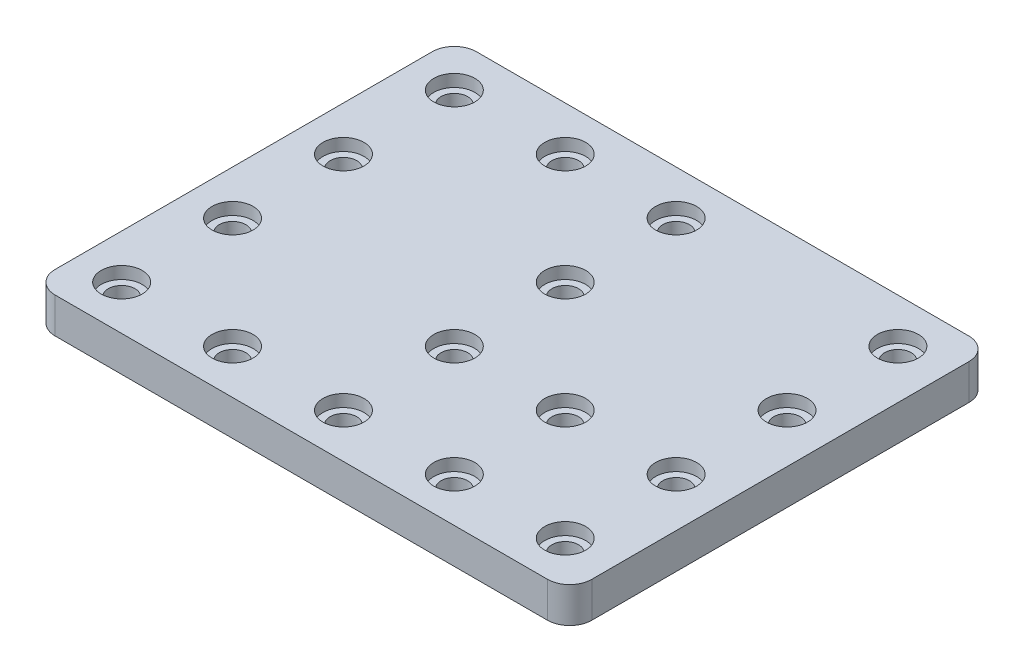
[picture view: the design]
ISO-10303-21;
HEADER;
FILE_DESCRIPTION(('STEP AP214'),'2;1');
FILE_NAME('part.step','',(''),(''),'','','');
FILE_SCHEMA(('AUTOMOTIVE_DESIGN { 1 0 10303 214 1 1 1 1 }'));
ENDSEC;
DATA;
#1=APPLICATION_CONTEXT('core data for automotive mechanical design processes');
#2=APPLICATION_PROTOCOL_DEFINITION('international standard','automotive_design',2000,#1);
#3=PRODUCT_CONTEXT('',#1,'mechanical');
#4=PRODUCT('Part','Part','',(#3));
#5=PRODUCT_RELATED_PRODUCT_CATEGORY('part','',(#4));
#6=PRODUCT_DEFINITION_FORMATION('','',#4);
#7=PRODUCT_DEFINITION_CONTEXT('part definition',#1,'design');
#8=PRODUCT_DEFINITION('design','',#6,#7);
#9=PRODUCT_DEFINITION_SHAPE('','',#8);
#10=(LENGTH_UNIT() NAMED_UNIT(*) SI_UNIT(.MILLI.,.METRE.));
#11=(NAMED_UNIT(*) PLANE_ANGLE_UNIT() SI_UNIT($,.RADIAN.));
#12=(NAMED_UNIT(*) SI_UNIT($,.STERADIAN.) SOLID_ANGLE_UNIT());
#13=UNCERTAINTY_MEASURE_WITH_UNIT(LENGTH_MEASURE(1.E-05),#10,'distance_accuracy_value','');
#14=(GEOMETRIC_REPRESENTATION_CONTEXT(3) GLOBAL_UNCERTAINTY_ASSIGNED_CONTEXT((#13)) GLOBAL_UNIT_ASSIGNED_CONTEXT((#10,
#11,#12)) REPRESENTATION_CONTEXT('',''));
#15=CARTESIAN_POINT('',(0.,0.,0.));
#16=DIRECTION('',(0.,0.,1.));
#17=DIRECTION('',(1.,0.,0.));
#18=AXIS2_PLACEMENT_3D('',#15,#16,#17);
#19=CARTESIAN_POINT('',(10.,16.,-10.));
#20=DIRECTION('',(0.,-1.,0.));
#21=DIRECTION('',(0.,0.,-1.));
#22=AXIS2_PLACEMENT_3D('',#19,#20,#21);
#23=CYLINDRICAL_SURFACE('',#22,10.);
#24=CARTESIAN_POINT('',(10.,0.,-10.));
#25=DIRECTION('',(0.,1.,0.));
#26=DIRECTION('',(0.,0.,-1.));
#27=AXIS2_PLACEMENT_3D('',#24,#25,#26);
#28=CIRCLE('',#27,10.);
#29=CARTESIAN_POINT('',(0.,0.,-10.));
#30=VERTEX_POINT('',#29);
#31=CARTESIAN_POINT('',(10.,0.,0.));
#32=VERTEX_POINT('',#31);
#33=EDGE_CURVE('E104',#30,#32,#28,.T.);
#34=ORIENTED_EDGE('',*,*,#33,.T.);
#35=DIRECTION('',(0.,-1.,0.));
#36=VECTOR('',#35,1.);
#37=CARTESIAN_POINT('',(10.,16.,0.));
#38=LINE('',#37,#36);
#39=CARTESIAN_POINT('',(10.,16.,0.));
#40=VERTEX_POINT('',#39);
#41=EDGE_CURVE('E112',#40,#32,#38,.T.);
#42=ORIENTED_EDGE('',*,*,#41,.F.);
#43=CARTESIAN_POINT('',(10.,16.,-10.));
#44=DIRECTION('',(0.,1.,0.));
#45=DIRECTION('',(0.,0.,-1.));
#46=AXIS2_PLACEMENT_3D('',#43,#44,#45);
#47=CIRCLE('',#46,10.);
#48=CARTESIAN_POINT('',(0.,16.,-10.));
#49=VERTEX_POINT('',#48);
#50=EDGE_CURVE('E140',#49,#40,#47,.T.);
#51=ORIENTED_EDGE('',*,*,#50,.F.);
#52=DIRECTION('',(0.,-1.,0.));
#53=VECTOR('',#52,1.);
#54=CARTESIAN_POINT('',(0.,16.,-10.));
#55=LINE('',#54,#53);
#56=EDGE_CURVE('E121',#49,#30,#55,.T.);
#57=ORIENTED_EDGE('',*,*,#56,.T.);
#58=EDGE_LOOP('',(#34,#42,#51,#57));
#59=FACE_BOUND('',#58,.T.);
#60=ADVANCED_FACE('F33',(#59),#23,.T.);
#61=CARTESIAN_POINT('',(10.,16.,0.));
#62=DIRECTION('',(0.,0.,-1.));
#63=DIRECTION('',(-1.,0.,0.));
#64=AXIS2_PLACEMENT_3D('',#61,#62,#63);
#65=PLANE('',#64);
#66=DIRECTION('',(1.,0.,0.));
#67=VECTOR('',#66,1.);
#68=CARTESIAN_POINT('',(10.,0.,0.));
#69=LINE('',#68,#67);
#70=CARTESIAN_POINT('',(232.,0.,0.));
#71=VERTEX_POINT('',#70);
#72=EDGE_CURVE('E98',#32,#71,#69,.T.);
#73=ORIENTED_EDGE('',*,*,#72,.T.);
#74=DIRECTION('',(0.,-1.,0.));
#75=VECTOR('',#74,1.);
#76=CARTESIAN_POINT('',(232.,16.,0.));
#77=LINE('',#76,#75);
#78=CARTESIAN_POINT('',(232.,16.,0.));
#79=VERTEX_POINT('',#78);
#80=EDGE_CURVE('E118',#79,#71,#77,.T.);
#81=ORIENTED_EDGE('',*,*,#80,.F.);
#82=DIRECTION('',(1.,0.,0.));
#83=VECTOR('',#82,1.);
#84=CARTESIAN_POINT('',(10.,16.,0.));
#85=LINE('',#84,#83);
#86=EDGE_CURVE('E114',#40,#79,#85,.T.);
#87=ORIENTED_EDGE('',*,*,#86,.F.);
#88=ORIENTED_EDGE('',*,*,#41,.T.);
#89=EDGE_LOOP('',(#73,#81,#87,#88));
#90=FACE_BOUND('',#89,.T.);
#91=ADVANCED_FACE('F113',(#90),#65,.F.);
#92=CARTESIAN_POINT('',(232.,16.,-10.));
#93=DIRECTION('',(0.,-1.,0.));
#94=DIRECTION('',(0.,0.,-1.));
#95=AXIS2_PLACEMENT_3D('',#92,#93,#94);
#96=CYLINDRICAL_SURFACE('',#95,10.);
#97=CARTESIAN_POINT('',(232.,0.,-10.));
#98=DIRECTION('',(0.,1.,0.));
#99=DIRECTION('',(0.,0.,1.));
#100=AXIS2_PLACEMENT_3D('',#97,#98,#99);
#101=CIRCLE('',#100,10.);
#102=CARTESIAN_POINT('',(242.,0.,-10.));
#103=VERTEX_POINT('',#102);
#104=EDGE_CURVE('E106',#71,#103,#101,.T.);
#105=ORIENTED_EDGE('',*,*,#104,.T.);
#106=DIRECTION('',(0.,-1.,0.));
#107=VECTOR('',#106,1.);
#108=CARTESIAN_POINT('',(242.,16.,-10.));
#109=LINE('',#108,#107);
#110=CARTESIAN_POINT('',(242.,16.,-10.));
#111=VERTEX_POINT('',#110);
#112=EDGE_CURVE('E166',#111,#103,#109,.T.);
#113=ORIENTED_EDGE('',*,*,#112,.F.);
#114=CARTESIAN_POINT('',(232.,16.,-10.));
#115=DIRECTION('',(0.,1.,0.));
#116=DIRECTION('',(0.,0.,1.));
#117=AXIS2_PLACEMENT_3D('',#114,#115,#116);
#118=CIRCLE('',#117,10.);
#119=EDGE_CURVE('E143',#79,#111,#118,.T.);
#120=ORIENTED_EDGE('',*,*,#119,.F.);
#121=ORIENTED_EDGE('',*,*,#80,.T.);
#122=EDGE_LOOP('',(#105,#113,#120,#121));
#123=FACE_BOUND('',#122,.T.);
#124=ADVANCED_FACE('F355',(#123),#96,.T.);
#125=CARTESIAN_POINT('',(242.,16.,-10.));
#126=DIRECTION('',(-1.,0.,0.));
#127=DIRECTION('',(0.,0.,1.));
#128=AXIS2_PLACEMENT_3D('',#125,#126,#127);
#129=PLANE('',#128);
#130=DIRECTION('',(0.,0.,-1.));
#131=VECTOR('',#130,1.);
#132=CARTESIAN_POINT('',(242.,0.,-10.));
#133=LINE('',#132,#131);
#134=CARTESIAN_POINT('',(242.,0.,-180.));
#135=VERTEX_POINT('',#134);
#136=EDGE_CURVE('E130',#103,#135,#133,.T.);
#137=ORIENTED_EDGE('',*,*,#136,.T.);
#138=DIRECTION('',(0.,-1.,0.));
#139=VECTOR('',#138,1.);
#140=CARTESIAN_POINT('',(242.,16.,-180.));
#141=LINE('',#140,#139);
#142=CARTESIAN_POINT('',(242.,16.,-180.));
#143=VERTEX_POINT('',#142);
#144=EDGE_CURVE('E163',#143,#135,#141,.T.);
#145=ORIENTED_EDGE('',*,*,#144,.F.);
#146=DIRECTION('',(0.,0.,-1.));
#147=VECTOR('',#146,1.);
#148=CARTESIAN_POINT('',(242.,16.,-10.));
#149=LINE('',#148,#147);
#150=EDGE_CURVE('E145',#111,#143,#149,.T.);
#151=ORIENTED_EDGE('',*,*,#150,.F.);
#152=ORIENTED_EDGE('',*,*,#112,.T.);
#153=EDGE_LOOP('',(#137,#145,#151,#152));
#154=FACE_BOUND('',#153,.T.);
#155=ADVANCED_FACE('F870',(#154),#129,.F.);
#156=CARTESIAN_POINT('',(232.,16.,-180.));
#157=DIRECTION('',(0.,-1.,0.));
#158=DIRECTION('',(0.,0.,-1.));
#159=AXIS2_PLACEMENT_3D('',#156,#157,#158);
#160=CYLINDRICAL_SURFACE('',#159,10.);
#161=CARTESIAN_POINT('',(232.,0.,-180.));
#162=DIRECTION('',(0.,1.,0.));
#163=DIRECTION('',(0.,0.,1.));
#164=AXIS2_PLACEMENT_3D('',#161,#162,#163);
#165=CIRCLE('',#164,10.);
#166=CARTESIAN_POINT('',(232.,0.,-190.));
#167=VERTEX_POINT('',#166);
#168=EDGE_CURVE('E132',#135,#167,#165,.T.);
#169=ORIENTED_EDGE('',*,*,#168,.T.);
#170=DIRECTION('',(0.,-1.,0.));
#171=VECTOR('',#170,1.);
#172=CARTESIAN_POINT('',(232.,16.,-190.));
#173=LINE('',#172,#171);
#174=CARTESIAN_POINT('',(232.,16.,-190.));
#175=VERTEX_POINT('',#174);
#176=EDGE_CURVE('E160',#175,#167,#173,.T.);
#177=ORIENTED_EDGE('',*,*,#176,.F.);
#178=CARTESIAN_POINT('',(232.,16.,-180.));
#179=DIRECTION('',(0.,1.,0.));
#180=DIRECTION('',(0.,0.,1.));
#181=AXIS2_PLACEMENT_3D('',#178,#179,#180);
#182=CIRCLE('',#181,10.);
#183=EDGE_CURVE('E147',#143,#175,#182,.T.);
#184=ORIENTED_EDGE('',*,*,#183,.F.);
#185=ORIENTED_EDGE('',*,*,#144,.T.);
#186=EDGE_LOOP('',(#169,#177,#184,#185));
#187=FACE_BOUND('',#186,.T.);
#188=ADVANCED_FACE('F861',(#187),#160,.T.);
#189=CARTESIAN_POINT('',(10.,16.,-190.));
#190=DIRECTION('',(0.,0.,1.));
#191=DIRECTION('',(1.,0.,0.));
#192=AXIS2_PLACEMENT_3D('',#189,#190,#191);
#193=PLANE('',#192);
#194=DIRECTION('',(-1.,0.,0.));
#195=VECTOR('',#194,1.);
#196=CARTESIAN_POINT('',(10.,0.,-190.));
#197=LINE('',#196,#195);
#198=CARTESIAN_POINT('',(10.,0.,-190.));
#199=VERTEX_POINT('',#198);
#200=EDGE_CURVE('E134',#167,#199,#197,.T.);
#201=ORIENTED_EDGE('',*,*,#200,.T.);
#202=DIRECTION('',(0.,-1.,0.));
#203=VECTOR('',#202,1.);
#204=CARTESIAN_POINT('',(10.,16.,-190.));
#205=LINE('',#204,#203);
#206=CARTESIAN_POINT('',(10.,16.,-190.));
#207=VERTEX_POINT('',#206);
#208=EDGE_CURVE('E157',#207,#199,#205,.T.);
#209=ORIENTED_EDGE('',*,*,#208,.F.);
#210=DIRECTION('',(-1.,0.,0.));
#211=VECTOR('',#210,1.);
#212=CARTESIAN_POINT('',(10.,16.,-190.));
#213=LINE('',#212,#211);
#214=EDGE_CURVE('E149',#175,#207,#213,.T.);
#215=ORIENTED_EDGE('',*,*,#214,.F.);
#216=ORIENTED_EDGE('',*,*,#176,.T.);
#217=EDGE_LOOP('',(#201,#209,#215,#216));
#218=FACE_BOUND('',#217,.T.);
#219=ADVANCED_FACE('F852',(#218),#193,.F.);
#220=CARTESIAN_POINT('',(10.,16.,-180.));
#221=DIRECTION('',(0.,-1.,0.));
#222=DIRECTION('',(0.,0.,-1.));
#223=AXIS2_PLACEMENT_3D('',#220,#221,#222);
#224=CYLINDRICAL_SURFACE('',#223,10.);
#225=CARTESIAN_POINT('',(10.,0.,-180.));
#226=DIRECTION('',(0.,1.,0.));
#227=DIRECTION('',(0.,0.,1.));
#228=AXIS2_PLACEMENT_3D('',#225,#226,#227);
#229=CIRCLE('',#228,10.);
#230=CARTESIAN_POINT('',(0.,0.,-180.));
#231=VERTEX_POINT('',#230);
#232=EDGE_CURVE('E136',#199,#231,#229,.T.);
#233=ORIENTED_EDGE('',*,*,#232,.T.);
#234=DIRECTION('',(0.,-1.,0.));
#235=VECTOR('',#234,1.);
#236=CARTESIAN_POINT('',(0.,16.,-180.));
#237=LINE('',#236,#235);
#238=CARTESIAN_POINT('',(0.,16.,-180.));
#239=VERTEX_POINT('',#238);
#240=EDGE_CURVE('E154',#239,#231,#237,.T.);
#241=ORIENTED_EDGE('',*,*,#240,.F.);
#242=CARTESIAN_POINT('',(10.,16.,-180.));
#243=DIRECTION('',(0.,1.,0.));
#244=DIRECTION('',(0.,0.,1.));
#245=AXIS2_PLACEMENT_3D('',#242,#243,#244);
#246=CIRCLE('',#245,10.);
#247=EDGE_CURVE('E53',#207,#239,#246,.T.);
#248=ORIENTED_EDGE('',*,*,#247,.F.);
#249=ORIENTED_EDGE('',*,*,#208,.T.);
#250=EDGE_LOOP('',(#233,#241,#248,#249));
#251=FACE_BOUND('',#250,.T.);
#252=ADVANCED_FACE('F345',(#251),#224,.T.);
#253=CARTESIAN_POINT('',(0.,16.,-10.));
#254=DIRECTION('',(1.,0.,0.));
#255=DIRECTION('',(0.,0.,-1.));
#256=AXIS2_PLACEMENT_3D('',#253,#254,#255);
#257=PLANE('',#256);
#258=DIRECTION('',(0.,0.,1.));
#259=VECTOR('',#258,1.);
#260=CARTESIAN_POINT('',(0.,0.,-10.));
#261=LINE('',#260,#259);
#262=EDGE_CURVE('E138',#231,#30,#261,.T.);
#263=ORIENTED_EDGE('',*,*,#262,.T.);
#264=ORIENTED_EDGE('',*,*,#56,.F.);
#265=DIRECTION('',(0.,0.,1.));
#266=VECTOR('',#265,1.);
#267=CARTESIAN_POINT('',(0.,16.,-10.));
#268=LINE('',#267,#266);
#269=EDGE_CURVE('E48',#239,#49,#268,.T.);
#270=ORIENTED_EDGE('',*,*,#269,.F.);
#271=ORIENTED_EDGE('',*,*,#240,.T.);
#272=EDGE_LOOP('',(#263,#264,#270,#271));
#273=FACE_BOUND('',#272,.T.);
#274=ADVANCED_FACE('F335',(#273),#257,.F.);
#275=CARTESIAN_POINT('',(10.,16.,-10.));
#276=DIRECTION('',(0.,-1.,0.));
#277=DIRECTION('',(0.,0.,-1.));
#278=AXIS2_PLACEMENT_3D('',#275,#276,#277);
#279=PLANE('',#278);
#280=CARTESIAN_POINT('',(20.,16.,-70.));
#281=DIRECTION('',(0.,1.,0.));
#282=DIRECTION('',(0.,0.,1.));
#283=AXIS2_PLACEMENT_3D('',#280,#281,#282);
#284=CIRCLE('',#283,9.24999999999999);
#285=CARTESIAN_POINT('',(20.,16.,-60.75));
#286=VERTEX_POINT('',#285);
#287=EDGE_CURVE('E983',#286,#286,#284,.T.);
#288=ORIENTED_EDGE('',*,*,#287,.F.);
#289=EDGE_LOOP('',(#288));
#290=FACE_BOUND('',#289,.T.);
#291=CARTESIAN_POINT('',(120.,16.,-70.));
#292=DIRECTION('',(0.,1.,0.));
#293=DIRECTION('',(0.,0.,1.));
#294=AXIS2_PLACEMENT_3D('',#291,#292,#293);
#295=CIRCLE('',#294,9.24999999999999);
#296=CARTESIAN_POINT('',(120.,16.,-60.75));
#297=VERTEX_POINT('',#296);
#298=EDGE_CURVE('E971',#297,#297,#295,.T.);
#299=ORIENTED_EDGE('',*,*,#298,.F.);
#300=EDGE_LOOP('',(#299));
#301=FACE_BOUND('',#300,.T.);
#302=CARTESIAN_POINT('',(20.,16.,-20.));
#303=DIRECTION('',(0.,1.,0.));
#304=DIRECTION('',(0.,0.,1.));
#305=AXIS2_PLACEMENT_3D('',#302,#303,#304);
#306=CIRCLE('',#305,9.24999999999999);
#307=CARTESIAN_POINT('',(20.,16.,-10.75));
#308=VERTEX_POINT('',#307);
#309=EDGE_CURVE('E957',#308,#308,#306,.T.);
#310=ORIENTED_EDGE('',*,*,#309,.F.);
#311=EDGE_LOOP('',(#310));
#312=FACE_BOUND('',#311,.T.);
#313=ORIENTED_EDGE('',*,*,#50,.T.);
#314=ORIENTED_EDGE('',*,*,#86,.T.);
#315=ORIENTED_EDGE('',*,*,#119,.T.);
#316=ORIENTED_EDGE('',*,*,#150,.T.);
#317=ORIENTED_EDGE('',*,*,#183,.T.);
#318=ORIENTED_EDGE('',*,*,#214,.T.);
#319=ORIENTED_EDGE('',*,*,#247,.T.);
#320=ORIENTED_EDGE('',*,*,#269,.T.);
#321=EDGE_LOOP('',(#313,#314,#315,#316,#317,#318,#319,#320));
#322=FACE_BOUND('',#321,.T.);
#323=CARTESIAN_POINT('',(120.,16.,-120.));
#324=DIRECTION('',(0.,1.,0.));
#325=DIRECTION('',(0.,0.,1.));
#326=AXIS2_PLACEMENT_3D('',#323,#324,#325);
#327=CIRCLE('',#326,9.24999999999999);
#328=CARTESIAN_POINT('',(120.,16.,-110.75));
#329=VERTEX_POINT('',#328);
#330=EDGE_CURVE('E117',#329,#329,#327,.T.);
#331=ORIENTED_EDGE('',*,*,#330,.F.);
#332=EDGE_LOOP('',(#331));
#333=FACE_BOUND('',#332,.T.);
#334=CARTESIAN_POINT('',(170.,16.,-70.));
#335=DIRECTION('',(0.,1.,0.));
#336=DIRECTION('',(0.,0.,1.));
#337=AXIS2_PLACEMENT_3D('',#334,#335,#336);
#338=CIRCLE('',#337,9.24999999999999);
#339=CARTESIAN_POINT('',(170.,16.,-60.75));
#340=VERTEX_POINT('',#339);
#341=EDGE_CURVE('E181',#340,#340,#338,.T.);
#342=ORIENTED_EDGE('',*,*,#341,.F.);
#343=EDGE_LOOP('',(#342));
#344=FACE_BOUND('',#343,.T.);
#345=CARTESIAN_POINT('',(20.,16.,-120.));
#346=DIRECTION('',(0.,1.,0.));
#347=DIRECTION('',(0.,0.,1.));
#348=AXIS2_PLACEMENT_3D('',#345,#346,#347);
#349=CIRCLE('',#348,9.24999999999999);
#350=CARTESIAN_POINT('',(20.,16.,-110.75));
#351=VERTEX_POINT('',#350);
#352=EDGE_CURVE('E193',#351,#351,#349,.T.);
#353=ORIENTED_EDGE('',*,*,#352,.F.);
#354=EDGE_LOOP('',(#353));
#355=FACE_BOUND('',#354,.T.);
#356=CARTESIAN_POINT('',(20.,16.,-170.));
#357=DIRECTION('',(0.,1.,0.));
#358=DIRECTION('',(0.,0.,1.));
#359=AXIS2_PLACEMENT_3D('',#356,#357,#358);
#360=CIRCLE('',#359,9.24999999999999);
#361=CARTESIAN_POINT('',(20.,16.,-160.75));
#362=VERTEX_POINT('',#361);
#363=EDGE_CURVE('E205',#362,#362,#360,.T.);
#364=ORIENTED_EDGE('',*,*,#363,.F.);
#365=EDGE_LOOP('',(#364));
#366=FACE_BOUND('',#365,.T.);
#367=CARTESIAN_POINT('',(70.,16.,-20.));
#368=DIRECTION('',(0.,1.,0.));
#369=DIRECTION('',(0.,0.,1.));
#370=AXIS2_PLACEMENT_3D('',#367,#368,#369);
#371=CIRCLE('',#370,9.24999999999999);
#372=CARTESIAN_POINT('',(70.,16.,-10.75));
#373=VERTEX_POINT('',#372);
#374=EDGE_CURVE('E217',#373,#373,#371,.T.);
#375=ORIENTED_EDGE('',*,*,#374,.F.);
#376=EDGE_LOOP('',(#375));
#377=FACE_BOUND('',#376,.T.);
#378=CARTESIAN_POINT('',(70.,16.,-170.));
#379=DIRECTION('',(0.,1.,0.));
#380=DIRECTION('',(0.,0.,1.));
#381=AXIS2_PLACEMENT_3D('',#378,#379,#380);
#382=CIRCLE('',#381,9.24999999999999);
#383=CARTESIAN_POINT('',(70.,16.,-160.75));
#384=VERTEX_POINT('',#383);
#385=EDGE_CURVE('E229',#384,#384,#382,.T.);
#386=ORIENTED_EDGE('',*,*,#385,.F.);
#387=EDGE_LOOP('',(#386));
#388=FACE_BOUND('',#387,.T.);
#389=CARTESIAN_POINT('',(120.,16.,-20.));
#390=DIRECTION('',(0.,1.,0.));
#391=DIRECTION('',(0.,0.,1.));
#392=AXIS2_PLACEMENT_3D('',#389,#390,#391);
#393=CIRCLE('',#392,9.24999999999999);
#394=CARTESIAN_POINT('',(120.,16.,-10.75));
#395=VERTEX_POINT('',#394);
#396=EDGE_CURVE('E241',#395,#395,#393,.T.);
#397=ORIENTED_EDGE('',*,*,#396,.F.);
#398=EDGE_LOOP('',(#397));
#399=FACE_BOUND('',#398,.T.);
#400=CARTESIAN_POINT('',(120.,16.,-170.));
#401=DIRECTION('',(0.,1.,0.));
#402=DIRECTION('',(0.,0.,1.));
#403=AXIS2_PLACEMENT_3D('',#400,#401,#402);
#404=CIRCLE('',#403,9.24999999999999);
#405=CARTESIAN_POINT('',(120.,16.,-160.75));
#406=VERTEX_POINT('',#405);
#407=EDGE_CURVE('E253',#406,#406,#404,.T.);
#408=ORIENTED_EDGE('',*,*,#407,.F.);
#409=EDGE_LOOP('',(#408));
#410=FACE_BOUND('',#409,.T.);
#411=CARTESIAN_POINT('',(170.,16.,-20.));
#412=DIRECTION('',(0.,1.,0.));
#413=DIRECTION('',(0.,0.,1.));
#414=AXIS2_PLACEMENT_3D('',#411,#412,#413);
#415=CIRCLE('',#414,9.24999999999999);
#416=CARTESIAN_POINT('',(170.,16.,-10.75));
#417=VERTEX_POINT('',#416);
#418=EDGE_CURVE('E265',#417,#417,#415,.T.);
#419=ORIENTED_EDGE('',*,*,#418,.F.);
#420=EDGE_LOOP('',(#419));
#421=FACE_BOUND('',#420,.T.);
#422=CARTESIAN_POINT('',(220.,16.,-20.));
#423=DIRECTION('',(0.,1.,0.));
#424=DIRECTION('',(0.,0.,1.));
#425=AXIS2_PLACEMENT_3D('',#422,#423,#424);
#426=CIRCLE('',#425,9.24999999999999);
#427=CARTESIAN_POINT('',(220.,16.,-10.75));
#428=VERTEX_POINT('',#427);
#429=EDGE_CURVE('E277',#428,#428,#426,.T.);
#430=ORIENTED_EDGE('',*,*,#429,.F.);
#431=EDGE_LOOP('',(#430));
#432=FACE_BOUND('',#431,.T.);
#433=CARTESIAN_POINT('',(220.,16.,-70.));
#434=DIRECTION('',(0.,1.,0.));
#435=DIRECTION('',(0.,0.,1.));
#436=AXIS2_PLACEMENT_3D('',#433,#434,#435);
#437=CIRCLE('',#436,9.24999999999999);
#438=CARTESIAN_POINT('',(220.,16.,-60.75));
#439=VERTEX_POINT('',#438);
#440=EDGE_CURVE('E289',#439,#439,#437,.T.);
#441=ORIENTED_EDGE('',*,*,#440,.F.);
#442=EDGE_LOOP('',(#441));
#443=FACE_BOUND('',#442,.T.);
#444=CARTESIAN_POINT('',(220.,16.,-120.));
#445=DIRECTION('',(0.,1.,0.));
#446=DIRECTION('',(0.,0.,1.));
#447=AXIS2_PLACEMENT_3D('',#444,#445,#446);
#448=CIRCLE('',#447,9.24999999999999);
#449=CARTESIAN_POINT('',(220.,16.,-110.75));
#450=VERTEX_POINT('',#449);
#451=EDGE_CURVE('E301',#450,#450,#448,.T.);
#452=ORIENTED_EDGE('',*,*,#451,.F.);
#453=EDGE_LOOP('',(#452));
#454=FACE_BOUND('',#453,.T.);
#455=CARTESIAN_POINT('',(220.,16.,-170.));
#456=DIRECTION('',(0.,1.,0.));
#457=DIRECTION('',(0.,0.,1.));
#458=AXIS2_PLACEMENT_3D('',#455,#456,#457);
#459=CIRCLE('',#458,9.24999999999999);
#460=CARTESIAN_POINT('',(220.,16.,-160.75));
#461=VERTEX_POINT('',#460);
#462=EDGE_CURVE('E313',#461,#461,#459,.T.);
#463=ORIENTED_EDGE('',*,*,#462,.F.);
#464=EDGE_LOOP('',(#463));
#465=FACE_BOUND('',#464,.T.);
#466=ADVANCED_FACE('F333',(#290,#301,#312,#322,#333,#344,#355,#366,#377,#388,#399,#410,#421,
#432,#443,#454,#465),#279,.F.);
#467=CARTESIAN_POINT('',(10.,0.,-10.));
#468=DIRECTION('',(0.,-1.,0.));
#469=DIRECTION('',(0.,0.,-1.));
#470=AXIS2_PLACEMENT_3D('',#467,#468,#469);
#471=PLANE('',#470);
#472=CARTESIAN_POINT('',(20.,0.,-70.));
#473=DIRECTION('',(0.,1.,0.));
#474=DIRECTION('',(0.,0.,1.));
#475=AXIS2_PLACEMENT_3D('',#472,#473,#474);
#476=CIRCLE('',#475,5.99999999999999);
#477=CARTESIAN_POINT('',(20.,0.,-64.));
#478=VERTEX_POINT('',#477);
#479=EDGE_CURVE('E980',#478,#478,#476,.T.);
#480=ORIENTED_EDGE('',*,*,#479,.T.);
#481=EDGE_LOOP('',(#480));
#482=FACE_BOUND('',#481,.T.);
#483=CARTESIAN_POINT('',(120.,0.,-70.));
#484=DIRECTION('',(0.,1.,0.));
#485=DIRECTION('',(0.,0.,1.));
#486=AXIS2_PLACEMENT_3D('',#483,#484,#485);
#487=CIRCLE('',#486,5.99999999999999);
#488=CARTESIAN_POINT('',(120.,0.,-64.));
#489=VERTEX_POINT('',#488);
#490=EDGE_CURVE('E968',#489,#489,#487,.T.);
#491=ORIENTED_EDGE('',*,*,#490,.T.);
#492=EDGE_LOOP('',(#491));
#493=FACE_BOUND('',#492,.T.);
#494=CARTESIAN_POINT('',(20.,0.,-20.));
#495=DIRECTION('',(0.,1.,0.));
#496=DIRECTION('',(0.,0.,1.));
#497=AXIS2_PLACEMENT_3D('',#494,#495,#496);
#498=CIRCLE('',#497,5.99999999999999);
#499=CARTESIAN_POINT('',(20.,0.,-14.));
#500=VERTEX_POINT('',#499);
#501=EDGE_CURVE('E122',#500,#500,#498,.T.);
#502=ORIENTED_EDGE('',*,*,#501,.T.);
#503=EDGE_LOOP('',(#502));
#504=FACE_BOUND('',#503,.T.);
#505=ORIENTED_EDGE('',*,*,#33,.F.);
#506=ORIENTED_EDGE('',*,*,#262,.F.);
#507=ORIENTED_EDGE('',*,*,#232,.F.);
#508=ORIENTED_EDGE('',*,*,#200,.F.);
#509=ORIENTED_EDGE('',*,*,#168,.F.);
#510=ORIENTED_EDGE('',*,*,#136,.F.);
#511=ORIENTED_EDGE('',*,*,#104,.F.);
#512=ORIENTED_EDGE('',*,*,#72,.F.);
#513=EDGE_LOOP('',(#505,#506,#507,#508,#509,#510,#511,#512));
#514=FACE_BOUND('',#513,.T.);
#515=CARTESIAN_POINT('',(120.,0.,-120.));
#516=DIRECTION('',(0.,1.,0.));
#517=DIRECTION('',(0.,0.,1.));
#518=AXIS2_PLACEMENT_3D('',#515,#516,#517);
#519=CIRCLE('',#518,5.99999999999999);
#520=CARTESIAN_POINT('',(120.,0.,-114.));
#521=VERTEX_POINT('',#520);
#522=EDGE_CURVE('E172',#521,#521,#519,.T.);
#523=ORIENTED_EDGE('',*,*,#522,.T.);
#524=EDGE_LOOP('',(#523));
#525=FACE_BOUND('',#524,.T.);
#526=CARTESIAN_POINT('',(170.,0.,-70.));
#527=DIRECTION('',(0.,1.,0.));
#528=DIRECTION('',(0.,0.,1.));
#529=AXIS2_PLACEMENT_3D('',#526,#527,#528);
#530=CIRCLE('',#529,5.99999999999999);
#531=CARTESIAN_POINT('',(170.,0.,-64.));
#532=VERTEX_POINT('',#531);
#533=EDGE_CURVE('E184',#532,#532,#530,.T.);
#534=ORIENTED_EDGE('',*,*,#533,.T.);
#535=EDGE_LOOP('',(#534));
#536=FACE_BOUND('',#535,.T.);
#537=CARTESIAN_POINT('',(20.,0.,-120.));
#538=DIRECTION('',(0.,1.,0.));
#539=DIRECTION('',(0.,0.,1.));
#540=AXIS2_PLACEMENT_3D('',#537,#538,#539);
#541=CIRCLE('',#540,5.99999999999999);
#542=CARTESIAN_POINT('',(20.,0.,-114.));
#543=VERTEX_POINT('',#542);
#544=EDGE_CURVE('E196',#543,#543,#541,.T.);
#545=ORIENTED_EDGE('',*,*,#544,.T.);
#546=EDGE_LOOP('',(#545));
#547=FACE_BOUND('',#546,.T.);
#548=CARTESIAN_POINT('',(20.,0.,-170.));
#549=DIRECTION('',(0.,1.,0.));
#550=DIRECTION('',(0.,0.,1.));
#551=AXIS2_PLACEMENT_3D('',#548,#549,#550);
#552=CIRCLE('',#551,5.99999999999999);
#553=CARTESIAN_POINT('',(20.,0.,-164.));
#554=VERTEX_POINT('',#553);
#555=EDGE_CURVE('E208',#554,#554,#552,.T.);
#556=ORIENTED_EDGE('',*,*,#555,.T.);
#557=EDGE_LOOP('',(#556));
#558=FACE_BOUND('',#557,.T.);
#559=CARTESIAN_POINT('',(70.,0.,-20.));
#560=DIRECTION('',(0.,1.,0.));
#561=DIRECTION('',(0.,0.,1.));
#562=AXIS2_PLACEMENT_3D('',#559,#560,#561);
#563=CIRCLE('',#562,5.99999999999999);
#564=CARTESIAN_POINT('',(70.,0.,-14.));
#565=VERTEX_POINT('',#564);
#566=EDGE_CURVE('E220',#565,#565,#563,.T.);
#567=ORIENTED_EDGE('',*,*,#566,.T.);
#568=EDGE_LOOP('',(#567));
#569=FACE_BOUND('',#568,.T.);
#570=CARTESIAN_POINT('',(70.,0.,-170.));
#571=DIRECTION('',(0.,1.,0.));
#572=DIRECTION('',(0.,0.,1.));
#573=AXIS2_PLACEMENT_3D('',#570,#571,#572);
#574=CIRCLE('',#573,5.99999999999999);
#575=CARTESIAN_POINT('',(70.,0.,-164.));
#576=VERTEX_POINT('',#575);
#577=EDGE_CURVE('E232',#576,#576,#574,.T.);
#578=ORIENTED_EDGE('',*,*,#577,.T.);
#579=EDGE_LOOP('',(#578));
#580=FACE_BOUND('',#579,.T.);
#581=CARTESIAN_POINT('',(120.,0.,-20.));
#582=DIRECTION('',(0.,1.,0.));
#583=DIRECTION('',(0.,0.,1.));
#584=AXIS2_PLACEMENT_3D('',#581,#582,#583);
#585=CIRCLE('',#584,5.99999999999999);
#586=CARTESIAN_POINT('',(120.,0.,-14.));
#587=VERTEX_POINT('',#586);
#588=EDGE_CURVE('E244',#587,#587,#585,.T.);
#589=ORIENTED_EDGE('',*,*,#588,.T.);
#590=EDGE_LOOP('',(#589));
#591=FACE_BOUND('',#590,.T.);
#592=CARTESIAN_POINT('',(120.,0.,-170.));
#593=DIRECTION('',(0.,1.,0.));
#594=DIRECTION('',(0.,0.,1.));
#595=AXIS2_PLACEMENT_3D('',#592,#593,#594);
#596=CIRCLE('',#595,5.99999999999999);
#597=CARTESIAN_POINT('',(120.,0.,-164.));
#598=VERTEX_POINT('',#597);
#599=EDGE_CURVE('E256',#598,#598,#596,.T.);
#600=ORIENTED_EDGE('',*,*,#599,.T.);
#601=EDGE_LOOP('',(#600));
#602=FACE_BOUND('',#601,.T.);
#603=CARTESIAN_POINT('',(170.,0.,-20.));
#604=DIRECTION('',(0.,1.,0.));
#605=DIRECTION('',(0.,0.,1.));
#606=AXIS2_PLACEMENT_3D('',#603,#604,#605);
#607=CIRCLE('',#606,5.99999999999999);
#608=CARTESIAN_POINT('',(170.,0.,-14.));
#609=VERTEX_POINT('',#608);
#610=EDGE_CURVE('E268',#609,#609,#607,.T.);
#611=ORIENTED_EDGE('',*,*,#610,.T.);
#612=EDGE_LOOP('',(#611));
#613=FACE_BOUND('',#612,.T.);
#614=CARTESIAN_POINT('',(220.,0.,-20.));
#615=DIRECTION('',(0.,1.,0.));
#616=DIRECTION('',(0.,0.,1.));
#617=AXIS2_PLACEMENT_3D('',#614,#615,#616);
#618=CIRCLE('',#617,5.99999999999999);
#619=CARTESIAN_POINT('',(220.,0.,-14.));
#620=VERTEX_POINT('',#619);
#621=EDGE_CURVE('E280',#620,#620,#618,.T.);
#622=ORIENTED_EDGE('',*,*,#621,.T.);
#623=EDGE_LOOP('',(#622));
#624=FACE_BOUND('',#623,.T.);
#625=CARTESIAN_POINT('',(220.,0.,-70.));
#626=DIRECTION('',(0.,1.,0.));
#627=DIRECTION('',(0.,0.,1.));
#628=AXIS2_PLACEMENT_3D('',#625,#626,#627);
#629=CIRCLE('',#628,5.99999999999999);
#630=CARTESIAN_POINT('',(220.,0.,-64.));
#631=VERTEX_POINT('',#630);
#632=EDGE_CURVE('E292',#631,#631,#629,.T.);
#633=ORIENTED_EDGE('',*,*,#632,.T.);
#634=EDGE_LOOP('',(#633));
#635=FACE_BOUND('',#634,.T.);
#636=CARTESIAN_POINT('',(220.,0.,-120.));
#637=DIRECTION('',(0.,1.,0.));
#638=DIRECTION('',(0.,0.,1.));
#639=AXIS2_PLACEMENT_3D('',#636,#637,#638);
#640=CIRCLE('',#639,5.99999999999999);
#641=CARTESIAN_POINT('',(220.,0.,-114.));
#642=VERTEX_POINT('',#641);
#643=EDGE_CURVE('E304',#642,#642,#640,.T.);
#644=ORIENTED_EDGE('',*,*,#643,.T.);
#645=EDGE_LOOP('',(#644));
#646=FACE_BOUND('',#645,.T.);
#647=CARTESIAN_POINT('',(220.,0.,-170.));
#648=DIRECTION('',(0.,1.,0.));
#649=DIRECTION('',(0.,0.,1.));
#650=AXIS2_PLACEMENT_3D('',#647,#648,#649);
#651=CIRCLE('',#650,5.99999999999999);
#652=CARTESIAN_POINT('',(220.,0.,-164.));
#653=VERTEX_POINT('',#652);
#654=EDGE_CURVE('E316',#653,#653,#651,.T.);
#655=ORIENTED_EDGE('',*,*,#654,.T.);
#656=EDGE_LOOP('',(#655));
#657=FACE_BOUND('',#656,.T.);
#658=ADVANCED_FACE('F100',(#482,#493,#504,#514,#525,#536,#547,#558,#569,#580,#591,#602,#613,
#624,#635,#646,#657),#471,.T.);
#659=CARTESIAN_POINT('',(20.,16.,-20.));
#660=DIRECTION('',(0.,1.,0.));
#661=DIRECTION('',(0.,0.,1.));
#662=AXIS2_PLACEMENT_3D('',#659,#660,#661);
#663=CYLINDRICAL_SURFACE('',#662,6.);
#664=ORIENTED_EDGE('',*,*,#501,.F.);
#665=EDGE_LOOP('',(#664));
#666=FACE_BOUND('',#665,.T.);
#667=CARTESIAN_POINT('',(20.,10.5,-20.));
#668=DIRECTION('',(0.,1.,0.));
#669=DIRECTION('',(0.,0.,1.));
#670=AXIS2_PLACEMENT_3D('',#667,#668,#669);
#671=CIRCLE('',#670,6.00000000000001);
#672=CARTESIAN_POINT('',(20.,10.5,-14.));
#673=VERTEX_POINT('',#672);
#674=EDGE_CURVE('E125',#673,#673,#671,.T.);
#675=ORIENTED_EDGE('',*,*,#674,.T.);
#676=EDGE_LOOP('',(#675));
#677=FACE_BOUND('',#676,.T.);
#678=ADVANCED_FACE('F342',(#666,#677),#663,.F.);
#679=CARTESIAN_POINT('',(26.,10.5,-20.));
#680=DIRECTION('',(0.,-1.,0.));
#681=DIRECTION('',(0.,0.,-1.));
#682=AXIS2_PLACEMENT_3D('',#679,#680,#681);
#683=PLANE('',#682);
#684=ORIENTED_EDGE('',*,*,#674,.F.);
#685=EDGE_LOOP('',(#684));
#686=FACE_BOUND('',#685,.T.);
#687=CARTESIAN_POINT('',(20.,10.5,-20.));
#688=DIRECTION('',(0.,1.,0.));
#689=DIRECTION('',(0.,0.,1.));
#690=AXIS2_PLACEMENT_3D('',#687,#688,#689);
#691=CIRCLE('',#690,9.24999999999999);
#692=CARTESIAN_POINT('',(20.,10.5,-10.75));
#693=VERTEX_POINT('',#692);
#694=EDGE_CURVE('E955',#693,#693,#691,.T.);
#695=ORIENTED_EDGE('',*,*,#694,.T.);
#696=EDGE_LOOP('',(#695));
#697=FACE_BOUND('',#696,.T.);
#698=ADVANCED_FACE('F716',(#686,#697),#683,.F.);
#699=CARTESIAN_POINT('',(20.,16.,-20.));
#700=DIRECTION('',(0.,1.,0.));
#701=DIRECTION('',(0.,0.,1.));
#702=AXIS2_PLACEMENT_3D('',#699,#700,#701);
#703=CYLINDRICAL_SURFACE('',#702,9.24999999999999);
#704=ORIENTED_EDGE('',*,*,#694,.F.);
#705=EDGE_LOOP('',(#704));
#706=FACE_BOUND('',#705,.T.);
#707=ORIENTED_EDGE('',*,*,#309,.T.);
#708=EDGE_LOOP('',(#707));
#709=FACE_BOUND('',#708,.T.);
#710=ADVANCED_FACE('F695',(#706,#709),#703,.F.);
#711=CARTESIAN_POINT('',(120.,16.,-70.));
#712=DIRECTION('',(0.,1.,0.));
#713=DIRECTION('',(0.,0.,1.));
#714=AXIS2_PLACEMENT_3D('',#711,#712,#713);
#715=CYLINDRICAL_SURFACE('',#714,6.);
#716=ORIENTED_EDGE('',*,*,#490,.F.);
#717=EDGE_LOOP('',(#716));
#718=FACE_BOUND('',#717,.T.);
#719=CARTESIAN_POINT('',(120.,10.5,-70.));
#720=DIRECTION('',(0.,1.,0.));
#721=DIRECTION('',(0.,0.,1.));
#722=AXIS2_PLACEMENT_3D('',#719,#720,#721);
#723=CIRCLE('',#722,6.00000000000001);
#724=CARTESIAN_POINT('',(120.,10.5,-64.));
#725=VERTEX_POINT('',#724);
#726=EDGE_CURVE('E962',#725,#725,#723,.T.);
#727=ORIENTED_EDGE('',*,*,#726,.T.);
#728=EDGE_LOOP('',(#727));
#729=FACE_BOUND('',#728,.T.);
#730=ADVANCED_FACE('F373',(#718,#729),#715,.F.);
#731=CARTESIAN_POINT('',(126.,10.5,-70.));
#732=DIRECTION('',(0.,-1.,0.));
#733=DIRECTION('',(0.,0.,-1.));
#734=AXIS2_PLACEMENT_3D('',#731,#732,#733);
#735=PLANE('',#734);
#736=ORIENTED_EDGE('',*,*,#726,.F.);
#737=EDGE_LOOP('',(#736));
#738=FACE_BOUND('',#737,.T.);
#739=CARTESIAN_POINT('',(120.,10.5,-70.));
#740=DIRECTION('',(0.,1.,0.));
#741=DIRECTION('',(0.,0.,1.));
#742=AXIS2_PLACEMENT_3D('',#739,#740,#741);
#743=CIRCLE('',#742,9.24999999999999);
#744=CARTESIAN_POINT('',(120.,10.5,-60.75));
#745=VERTEX_POINT('',#744);
#746=EDGE_CURVE('E965',#745,#745,#743,.T.);
#747=ORIENTED_EDGE('',*,*,#746,.T.);
#748=EDGE_LOOP('',(#747));
#749=FACE_BOUND('',#748,.T.);
#750=ADVANCED_FACE('F692',(#738,#749),#735,.F.);
#751=CARTESIAN_POINT('',(120.,16.,-70.));
#752=DIRECTION('',(0.,1.,0.));
#753=DIRECTION('',(0.,0.,1.));
#754=AXIS2_PLACEMENT_3D('',#751,#752,#753);
#755=CYLINDRICAL_SURFACE('',#754,9.24999999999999);
#756=ORIENTED_EDGE('',*,*,#746,.F.);
#757=EDGE_LOOP('',(#756));
#758=FACE_BOUND('',#757,.T.);
#759=ORIENTED_EDGE('',*,*,#298,.T.);
#760=EDGE_LOOP('',(#759));
#761=FACE_BOUND('',#760,.T.);
#762=ADVANCED_FACE('F371',(#758,#761),#755,.F.);
#763=CARTESIAN_POINT('',(120.,16.,-120.));
#764=DIRECTION('',(0.,1.,0.));
#765=DIRECTION('',(0.,0.,1.));
#766=AXIS2_PLACEMENT_3D('',#763,#764,#765);
#767=CYLINDRICAL_SURFACE('',#766,9.24999999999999);
#768=CARTESIAN_POINT('',(120.,10.5,-120.));
#769=DIRECTION('',(0.,1.,0.));
#770=DIRECTION('',(0.,0.,1.));
#771=AXIS2_PLACEMENT_3D('',#768,#769,#770);
#772=CIRCLE('',#771,9.24999999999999);
#773=CARTESIAN_POINT('',(120.,10.5,-110.75));
#774=VERTEX_POINT('',#773);
#775=EDGE_CURVE('E178',#774,#774,#772,.T.);
#776=ORIENTED_EDGE('',*,*,#775,.F.);
#777=EDGE_LOOP('',(#776));
#778=FACE_BOUND('',#777,.T.);
#779=ORIENTED_EDGE('',*,*,#330,.T.);
#780=EDGE_LOOP('',(#779));
#781=FACE_BOUND('',#780,.T.);
#782=ADVANCED_FACE('F367',(#778,#781),#767,.F.);
#783=CARTESIAN_POINT('',(126.,10.5,-120.));
#784=DIRECTION('',(0.,-1.,0.));
#785=DIRECTION('',(0.,0.,-1.));
#786=AXIS2_PLACEMENT_3D('',#783,#784,#785);
#787=PLANE('',#786);
#788=CARTESIAN_POINT('',(120.,10.5,-120.));
#789=DIRECTION('',(0.,1.,0.));
#790=DIRECTION('',(0.,0.,1.));
#791=AXIS2_PLACEMENT_3D('',#788,#789,#790);
#792=CIRCLE('',#791,6.00000000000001);
#793=CARTESIAN_POINT('',(120.,10.5,-114.));
#794=VERTEX_POINT('',#793);
#795=EDGE_CURVE('E175',#794,#794,#792,.T.);
#796=ORIENTED_EDGE('',*,*,#795,.F.);
#797=EDGE_LOOP('',(#796));
#798=FACE_BOUND('',#797,.T.);
#799=ORIENTED_EDGE('',*,*,#775,.T.);
#800=EDGE_LOOP('',(#799));
#801=FACE_BOUND('',#800,.T.);
#802=ADVANCED_FACE('F363',(#798,#801),#787,.F.);
#803=CARTESIAN_POINT('',(120.,16.,-120.));
#804=DIRECTION('',(0.,1.,0.));
#805=DIRECTION('',(0.,0.,1.));
#806=AXIS2_PLACEMENT_3D('',#803,#804,#805);
#807=CYLINDRICAL_SURFACE('',#806,6.);
#808=ORIENTED_EDGE('',*,*,#522,.F.);
#809=EDGE_LOOP('',(#808));
#810=FACE_BOUND('',#809,.T.);
#811=ORIENTED_EDGE('',*,*,#795,.T.);
#812=EDGE_LOOP('',(#811));
#813=FACE_BOUND('',#812,.T.);
#814=ADVANCED_FACE('F359',(#810,#813),#807,.F.);
#815=CARTESIAN_POINT('',(170.,16.,-70.));
#816=DIRECTION('',(0.,1.,0.));
#817=DIRECTION('',(0.,0.,1.));
#818=AXIS2_PLACEMENT_3D('',#815,#816,#817);
#819=CYLINDRICAL_SURFACE('',#818,9.24999999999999);
#820=CARTESIAN_POINT('',(170.,10.5,-70.));
#821=DIRECTION('',(0.,1.,0.));
#822=DIRECTION('',(0.,0.,1.));
#823=AXIS2_PLACEMENT_3D('',#820,#821,#822);
#824=CIRCLE('',#823,9.24999999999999);
#825=CARTESIAN_POINT('',(170.,10.5,-60.75));
#826=VERTEX_POINT('',#825);
#827=EDGE_CURVE('E190',#826,#826,#824,.T.);
#828=ORIENTED_EDGE('',*,*,#827,.F.);
#829=EDGE_LOOP('',(#828));
#830=FACE_BOUND('',#829,.T.);
#831=ORIENTED_EDGE('',*,*,#341,.T.);
#832=EDGE_LOOP('',(#831));
#833=FACE_BOUND('',#832,.T.);
#834=ADVANCED_FACE('F362',(#830,#833),#819,.F.);
#835=CARTESIAN_POINT('',(176.,10.5,-70.));
#836=DIRECTION('',(0.,-1.,0.));
#837=DIRECTION('',(0.,0.,-1.));
#838=AXIS2_PLACEMENT_3D('',#835,#836,#837);
#839=PLANE('',#838);
#840=CARTESIAN_POINT('',(170.,10.5,-70.));
#841=DIRECTION('',(0.,1.,0.));
#842=DIRECTION('',(0.,0.,1.));
#843=AXIS2_PLACEMENT_3D('',#840,#841,#842);
#844=CIRCLE('',#843,6.00000000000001);
#845=CARTESIAN_POINT('',(170.,10.5,-64.));
#846=VERTEX_POINT('',#845);
#847=EDGE_CURVE('E187',#846,#846,#844,.T.);
#848=ORIENTED_EDGE('',*,*,#847,.F.);
#849=EDGE_LOOP('',(#848));
#850=FACE_BOUND('',#849,.T.);
#851=ORIENTED_EDGE('',*,*,#827,.T.);
#852=EDGE_LOOP('',(#851));
#853=FACE_BOUND('',#852,.T.);
#854=ADVANCED_FACE('F378',(#850,#853),#839,.F.);
#855=CARTESIAN_POINT('',(170.,16.,-70.));
#856=DIRECTION('',(0.,1.,0.));
#857=DIRECTION('',(0.,0.,1.));
#858=AXIS2_PLACEMENT_3D('',#855,#856,#857);
#859=CYLINDRICAL_SURFACE('',#858,6.);
#860=ORIENTED_EDGE('',*,*,#533,.F.);
#861=EDGE_LOOP('',(#860));
#862=FACE_BOUND('',#861,.T.);
#863=ORIENTED_EDGE('',*,*,#847,.T.);
#864=EDGE_LOOP('',(#863));
#865=FACE_BOUND('',#864,.T.);
#866=ADVANCED_FACE('F374',(#862,#865),#859,.F.);
#867=CARTESIAN_POINT('',(20.,16.,-70.));
#868=DIRECTION('',(0.,1.,0.));
#869=DIRECTION('',(0.,0.,1.));
#870=AXIS2_PLACEMENT_3D('',#867,#868,#869);
#871=CYLINDRICAL_SURFACE('',#870,6.);
#872=ORIENTED_EDGE('',*,*,#479,.F.);
#873=EDGE_LOOP('',(#872));
#874=FACE_BOUND('',#873,.T.);
#875=CARTESIAN_POINT('',(20.,10.5,-70.));
#876=DIRECTION('',(0.,1.,0.));
#877=DIRECTION('',(0.,0.,1.));
#878=AXIS2_PLACEMENT_3D('',#875,#876,#877);
#879=CIRCLE('',#878,6.00000000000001);
#880=CARTESIAN_POINT('',(20.,10.5,-64.));
#881=VERTEX_POINT('',#880);
#882=EDGE_CURVE('E974',#881,#881,#879,.T.);
#883=ORIENTED_EDGE('',*,*,#882,.T.);
#884=EDGE_LOOP('',(#883));
#885=FACE_BOUND('',#884,.T.);
#886=ADVANCED_FACE('F377',(#874,#885),#871,.F.);
#887=CARTESIAN_POINT('',(26.,10.5,-70.));
#888=DIRECTION('',(0.,-1.,0.));
#889=DIRECTION('',(0.,0.,-1.));
#890=AXIS2_PLACEMENT_3D('',#887,#888,#889);
#891=PLANE('',#890);
#892=ORIENTED_EDGE('',*,*,#882,.F.);
#893=EDGE_LOOP('',(#892));
#894=FACE_BOUND('',#893,.T.);
#895=CARTESIAN_POINT('',(20.,10.5,-70.));
#896=DIRECTION('',(0.,1.,0.));
#897=DIRECTION('',(0.,0.,1.));
#898=AXIS2_PLACEMENT_3D('',#895,#896,#897);
#899=CIRCLE('',#898,9.24999999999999);
#900=CARTESIAN_POINT('',(20.,10.5,-60.75));
#901=VERTEX_POINT('',#900);
#902=EDGE_CURVE('E977',#901,#901,#899,.T.);
#903=ORIENTED_EDGE('',*,*,#902,.T.);
#904=EDGE_LOOP('',(#903));
#905=FACE_BOUND('',#904,.T.);
#906=ADVANCED_FACE('F646',(#894,#905),#891,.F.);
#907=CARTESIAN_POINT('',(20.,16.,-70.));
#908=DIRECTION('',(0.,1.,0.));
#909=DIRECTION('',(0.,0.,1.));
#910=AXIS2_PLACEMENT_3D('',#907,#908,#909);
#911=CYLINDRICAL_SURFACE('',#910,9.24999999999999);
#912=ORIENTED_EDGE('',*,*,#902,.F.);
#913=EDGE_LOOP('',(#912));
#914=FACE_BOUND('',#913,.T.);
#915=ORIENTED_EDGE('',*,*,#287,.T.);
#916=EDGE_LOOP('',(#915));
#917=FACE_BOUND('',#916,.T.);
#918=ADVANCED_FACE('F380',(#914,#917),#911,.F.);
#919=CARTESIAN_POINT('',(20.,16.,-120.));
#920=DIRECTION('',(0.,1.,0.));
#921=DIRECTION('',(0.,0.,1.));
#922=AXIS2_PLACEMENT_3D('',#919,#920,#921);
#923=CYLINDRICAL_SURFACE('',#922,9.24999999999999);
#924=CARTESIAN_POINT('',(20.,10.5,-120.));
#925=DIRECTION('',(0.,1.,0.));
#926=DIRECTION('',(0.,0.,1.));
#927=AXIS2_PLACEMENT_3D('',#924,#925,#926);
#928=CIRCLE('',#927,9.24999999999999);
#929=CARTESIAN_POINT('',(20.,10.5,-110.75));
#930=VERTEX_POINT('',#929);
#931=EDGE_CURVE('E202',#930,#930,#928,.T.);
#932=ORIENTED_EDGE('',*,*,#931,.F.);
#933=EDGE_LOOP('',(#932));
#934=FACE_BOUND('',#933,.T.);
#935=ORIENTED_EDGE('',*,*,#352,.T.);
#936=EDGE_LOOP('',(#935));
#937=FACE_BOUND('',#936,.T.);
#938=ADVANCED_FACE('F395',(#934,#937),#923,.F.);
#939=CARTESIAN_POINT('',(26.,10.5,-120.));
#940=DIRECTION('',(0.,-1.,0.));
#941=DIRECTION('',(0.,0.,-1.));
#942=AXIS2_PLACEMENT_3D('',#939,#940,#941);
#943=PLANE('',#942);
#944=CARTESIAN_POINT('',(20.,10.5,-120.));
#945=DIRECTION('',(0.,1.,0.));
#946=DIRECTION('',(0.,0.,1.));
#947=AXIS2_PLACEMENT_3D('',#944,#945,#946);
#948=CIRCLE('',#947,6.00000000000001);
#949=CARTESIAN_POINT('',(20.,10.5,-114.));
#950=VERTEX_POINT('',#949);
#951=EDGE_CURVE('E199',#950,#950,#948,.T.);
#952=ORIENTED_EDGE('',*,*,#951,.F.);
#953=EDGE_LOOP('',(#952));
#954=FACE_BOUND('',#953,.T.);
#955=ORIENTED_EDGE('',*,*,#931,.T.);
#956=EDGE_LOOP('',(#955));
#957=FACE_BOUND('',#956,.T.);
#958=ADVANCED_FACE('F391',(#954,#957),#943,.F.);
#959=CARTESIAN_POINT('',(20.,16.,-120.));
#960=DIRECTION('',(0.,1.,0.));
#961=DIRECTION('',(0.,0.,1.));
#962=AXIS2_PLACEMENT_3D('',#959,#960,#961);
#963=CYLINDRICAL_SURFACE('',#962,6.);
#964=ORIENTED_EDGE('',*,*,#544,.F.);
#965=EDGE_LOOP('',(#964));
#966=FACE_BOUND('',#965,.T.);
#967=ORIENTED_EDGE('',*,*,#951,.T.);
#968=EDGE_LOOP('',(#967));
#969=FACE_BOUND('',#968,.T.);
#970=ADVANCED_FACE('F387',(#966,#969),#963,.F.);
#971=CARTESIAN_POINT('',(20.,16.,-170.));
#972=DIRECTION('',(0.,1.,0.));
#973=DIRECTION('',(0.,0.,1.));
#974=AXIS2_PLACEMENT_3D('',#971,#972,#973);
#975=CYLINDRICAL_SURFACE('',#974,9.24999999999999);
#976=CARTESIAN_POINT('',(20.,10.5,-170.));
#977=DIRECTION('',(0.,1.,0.));
#978=DIRECTION('',(0.,0.,1.));
#979=AXIS2_PLACEMENT_3D('',#976,#977,#978);
#980=CIRCLE('',#979,9.24999999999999);
#981=CARTESIAN_POINT('',(20.,10.5,-160.75));
#982=VERTEX_POINT('',#981);
#983=EDGE_CURVE('E214',#982,#982,#980,.T.);
#984=ORIENTED_EDGE('',*,*,#983,.F.);
#985=EDGE_LOOP('',(#984));
#986=FACE_BOUND('',#985,.T.);
#987=ORIENTED_EDGE('',*,*,#363,.T.);
#988=EDGE_LOOP('',(#987));
#989=FACE_BOUND('',#988,.T.);
#990=ADVANCED_FACE('F390',(#986,#989),#975,.F.);
#991=CARTESIAN_POINT('',(26.,10.5,-170.));
#992=DIRECTION('',(0.,-1.,0.));
#993=DIRECTION('',(0.,0.,-1.));
#994=AXIS2_PLACEMENT_3D('',#991,#992,#993);
#995=PLANE('',#994);
#996=CARTESIAN_POINT('',(20.,10.5,-170.));
#997=DIRECTION('',(0.,1.,0.));
#998=DIRECTION('',(0.,0.,1.));
#999=AXIS2_PLACEMENT_3D('',#996,#997,#998);
#1000=CIRCLE('',#999,6.00000000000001);
#1001=CARTESIAN_POINT('',(20.,10.5,-164.));
#1002=VERTEX_POINT('',#1001);
#1003=EDGE_CURVE('E211',#1002,#1002,#1000,.T.);
#1004=ORIENTED_EDGE('',*,*,#1003,.F.);
#1005=EDGE_LOOP('',(#1004));
#1006=FACE_BOUND('',#1005,.T.);
#1007=ORIENTED_EDGE('',*,*,#983,.T.);
#1008=EDGE_LOOP('',(#1007));
#1009=FACE_BOUND('',#1008,.T.);
#1010=ADVANCED_FACE('F404',(#1006,#1009),#995,.F.);
#1011=CARTESIAN_POINT('',(20.,16.,-170.));
#1012=DIRECTION('',(0.,1.,0.));
#1013=DIRECTION('',(0.,0.,1.));
#1014=AXIS2_PLACEMENT_3D('',#1011,#1012,#1013);
#1015=CYLINDRICAL_SURFACE('',#1014,6.);
#1016=ORIENTED_EDGE('',*,*,#555,.F.);
#1017=EDGE_LOOP('',(#1016));
#1018=FACE_BOUND('',#1017,.T.);
#1019=ORIENTED_EDGE('',*,*,#1003,.T.);
#1020=EDGE_LOOP('',(#1019));
#1021=FACE_BOUND('',#1020,.T.);
#1022=ADVANCED_FACE('F400',(#1018,#1021),#1015,.F.);
#1023=CARTESIAN_POINT('',(70.,16.,-20.));
#1024=DIRECTION('',(0.,1.,0.));
#1025=DIRECTION('',(0.,0.,1.));
#1026=AXIS2_PLACEMENT_3D('',#1023,#1024,#1025);
#1027=CYLINDRICAL_SURFACE('',#1026,9.24999999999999);
#1028=CARTESIAN_POINT('',(70.,10.5,-20.));
#1029=DIRECTION('',(0.,1.,0.));
#1030=DIRECTION('',(0.,0.,1.));
#1031=AXIS2_PLACEMENT_3D('',#1028,#1029,#1030);
#1032=CIRCLE('',#1031,9.24999999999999);
#1033=CARTESIAN_POINT('',(70.,10.5,-10.75));
#1034=VERTEX_POINT('',#1033);
#1035=EDGE_CURVE('E226',#1034,#1034,#1032,.T.);
#1036=ORIENTED_EDGE('',*,*,#1035,.F.);
#1037=EDGE_LOOP('',(#1036));
#1038=FACE_BOUND('',#1037,.T.);
#1039=ORIENTED_EDGE('',*,*,#374,.T.);
#1040=EDGE_LOOP('',(#1039));
#1041=FACE_BOUND('',#1040,.T.);
#1042=ADVANCED_FACE('F403',(#1038,#1041),#1027,.F.);
#1043=CARTESIAN_POINT('',(76.,10.5,-20.));
#1044=DIRECTION('',(0.,-1.,0.));
#1045=DIRECTION('',(0.,0.,-1.));
#1046=AXIS2_PLACEMENT_3D('',#1043,#1044,#1045);
#1047=PLANE('',#1046);
#1048=CARTESIAN_POINT('',(70.,10.5,-20.));
#1049=DIRECTION('',(0.,1.,0.));
#1050=DIRECTION('',(0.,0.,1.));
#1051=AXIS2_PLACEMENT_3D('',#1048,#1049,#1050);
#1052=CIRCLE('',#1051,6.00000000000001);
#1053=CARTESIAN_POINT('',(70.,10.5,-14.));
#1054=VERTEX_POINT('',#1053);
#1055=EDGE_CURVE('E223',#1054,#1054,#1052,.T.);
#1056=ORIENTED_EDGE('',*,*,#1055,.F.);
#1057=EDGE_LOOP('',(#1056));
#1058=FACE_BOUND('',#1057,.T.);
#1059=ORIENTED_EDGE('',*,*,#1035,.T.);
#1060=EDGE_LOOP('',(#1059));
#1061=FACE_BOUND('',#1060,.T.);
#1062=ADVANCED_FACE('F416',(#1058,#1061),#1047,.F.);
#1063=CARTESIAN_POINT('',(70.,16.,-20.));
#1064=DIRECTION('',(0.,1.,0.));
#1065=DIRECTION('',(0.,0.,1.));
#1066=AXIS2_PLACEMENT_3D('',#1063,#1064,#1065);
#1067=CYLINDRICAL_SURFACE('',#1066,6.);
#1068=ORIENTED_EDGE('',*,*,#566,.F.);
#1069=EDGE_LOOP('',(#1068));
#1070=FACE_BOUND('',#1069,.T.);
#1071=ORIENTED_EDGE('',*,*,#1055,.T.);
#1072=EDGE_LOOP('',(#1071));
#1073=FACE_BOUND('',#1072,.T.);
#1074=ADVANCED_FACE('F412',(#1070,#1073),#1067,.F.);
#1075=CARTESIAN_POINT('',(70.,16.,-170.));
#1076=DIRECTION('',(0.,1.,0.));
#1077=DIRECTION('',(0.,0.,1.));
#1078=AXIS2_PLACEMENT_3D('',#1075,#1076,#1077);
#1079=CYLINDRICAL_SURFACE('',#1078,9.24999999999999);
#1080=CARTESIAN_POINT('',(70.,10.5,-170.));
#1081=DIRECTION('',(0.,1.,0.));
#1082=DIRECTION('',(0.,0.,1.));
#1083=AXIS2_PLACEMENT_3D('',#1080,#1081,#1082);
#1084=CIRCLE('',#1083,9.24999999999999);
#1085=CARTESIAN_POINT('',(70.,10.5,-160.75));
#1086=VERTEX_POINT('',#1085);
#1087=EDGE_CURVE('E238',#1086,#1086,#1084,.T.);
#1088=ORIENTED_EDGE('',*,*,#1087,.F.);
#1089=EDGE_LOOP('',(#1088));
#1090=FACE_BOUND('',#1089,.T.);
#1091=ORIENTED_EDGE('',*,*,#385,.T.);
#1092=EDGE_LOOP('',(#1091));
#1093=FACE_BOUND('',#1092,.T.);
#1094=ADVANCED_FACE('F415',(#1090,#1093),#1079,.F.);
#1095=CARTESIAN_POINT('',(76.,10.5,-170.));
#1096=DIRECTION('',(0.,-1.,0.));
#1097=DIRECTION('',(0.,0.,-1.));
#1098=AXIS2_PLACEMENT_3D('',#1095,#1096,#1097);
#1099=PLANE('',#1098);
#1100=CARTESIAN_POINT('',(70.,10.5,-170.));
#1101=DIRECTION('',(0.,1.,0.));
#1102=DIRECTION('',(0.,0.,1.));
#1103=AXIS2_PLACEMENT_3D('',#1100,#1101,#1102);
#1104=CIRCLE('',#1103,6.00000000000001);
#1105=CARTESIAN_POINT('',(70.,10.5,-164.));
#1106=VERTEX_POINT('',#1105);
#1107=EDGE_CURVE('E235',#1106,#1106,#1104,.T.);
#1108=ORIENTED_EDGE('',*,*,#1107,.F.);
#1109=EDGE_LOOP('',(#1108));
#1110=FACE_BOUND('',#1109,.T.);
#1111=ORIENTED_EDGE('',*,*,#1087,.T.);
#1112=EDGE_LOOP('',(#1111));
#1113=FACE_BOUND('',#1112,.T.);
#1114=ADVANCED_FACE('F428',(#1110,#1113),#1099,.F.);
#1115=CARTESIAN_POINT('',(70.,16.,-170.));
#1116=DIRECTION('',(0.,1.,0.));
#1117=DIRECTION('',(0.,0.,1.));
#1118=AXIS2_PLACEMENT_3D('',#1115,#1116,#1117);
#1119=CYLINDRICAL_SURFACE('',#1118,6.);
#1120=ORIENTED_EDGE('',*,*,#577,.F.);
#1121=EDGE_LOOP('',(#1120));
#1122=FACE_BOUND('',#1121,.T.);
#1123=ORIENTED_EDGE('',*,*,#1107,.T.);
#1124=EDGE_LOOP('',(#1123));
#1125=FACE_BOUND('',#1124,.T.);
#1126=ADVANCED_FACE('F424',(#1122,#1125),#1119,.F.);
#1127=CARTESIAN_POINT('',(120.,16.,-20.));
#1128=DIRECTION('',(0.,1.,0.));
#1129=DIRECTION('',(0.,0.,1.));
#1130=AXIS2_PLACEMENT_3D('',#1127,#1128,#1129);
#1131=CYLINDRICAL_SURFACE('',#1130,9.24999999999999);
#1132=CARTESIAN_POINT('',(120.,10.5,-20.));
#1133=DIRECTION('',(0.,1.,0.));
#1134=DIRECTION('',(0.,0.,1.));
#1135=AXIS2_PLACEMENT_3D('',#1132,#1133,#1134);
#1136=CIRCLE('',#1135,9.24999999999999);
#1137=CARTESIAN_POINT('',(120.,10.5,-10.75));
#1138=VERTEX_POINT('',#1137);
#1139=EDGE_CURVE('E250',#1138,#1138,#1136,.T.);
#1140=ORIENTED_EDGE('',*,*,#1139,.F.);
#1141=EDGE_LOOP('',(#1140));
#1142=FACE_BOUND('',#1141,.T.);
#1143=ORIENTED_EDGE('',*,*,#396,.T.);
#1144=EDGE_LOOP('',(#1143));
#1145=FACE_BOUND('',#1144,.T.);
#1146=ADVANCED_FACE('F427',(#1142,#1145),#1131,.F.);
#1147=CARTESIAN_POINT('',(126.,10.5,-20.));
#1148=DIRECTION('',(0.,-1.,0.));
#1149=DIRECTION('',(0.,0.,-1.));
#1150=AXIS2_PLACEMENT_3D('',#1147,#1148,#1149);
#1151=PLANE('',#1150);
#1152=CARTESIAN_POINT('',(120.,10.5,-20.));
#1153=DIRECTION('',(0.,1.,0.));
#1154=DIRECTION('',(0.,0.,1.));
#1155=AXIS2_PLACEMENT_3D('',#1152,#1153,#1154);
#1156=CIRCLE('',#1155,6.00000000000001);
#1157=CARTESIAN_POINT('',(120.,10.5,-14.));
#1158=VERTEX_POINT('',#1157);
#1159=EDGE_CURVE('E247',#1158,#1158,#1156,.T.);
#1160=ORIENTED_EDGE('',*,*,#1159,.F.);
#1161=EDGE_LOOP('',(#1160));
#1162=FACE_BOUND('',#1161,.T.);
#1163=ORIENTED_EDGE('',*,*,#1139,.T.);
#1164=EDGE_LOOP('',(#1163));
#1165=FACE_BOUND('',#1164,.T.);
#1166=ADVANCED_FACE('F440',(#1162,#1165),#1151,.F.);
#1167=CARTESIAN_POINT('',(120.,16.,-20.));
#1168=DIRECTION('',(0.,1.,0.));
#1169=DIRECTION('',(0.,0.,1.));
#1170=AXIS2_PLACEMENT_3D('',#1167,#1168,#1169);
#1171=CYLINDRICAL_SURFACE('',#1170,6.);
#1172=ORIENTED_EDGE('',*,*,#588,.F.);
#1173=EDGE_LOOP('',(#1172));
#1174=FACE_BOUND('',#1173,.T.);
#1175=ORIENTED_EDGE('',*,*,#1159,.T.);
#1176=EDGE_LOOP('',(#1175));
#1177=FACE_BOUND('',#1176,.T.);
#1178=ADVANCED_FACE('F436',(#1174,#1177),#1171,.F.);
#1179=CARTESIAN_POINT('',(120.,16.,-170.));
#1180=DIRECTION('',(0.,1.,0.));
#1181=DIRECTION('',(0.,0.,1.));
#1182=AXIS2_PLACEMENT_3D('',#1179,#1180,#1181);
#1183=CYLINDRICAL_SURFACE('',#1182,9.24999999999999);
#1184=CARTESIAN_POINT('',(120.,10.5,-170.));
#1185=DIRECTION('',(0.,1.,0.));
#1186=DIRECTION('',(0.,0.,1.));
#1187=AXIS2_PLACEMENT_3D('',#1184,#1185,#1186);
#1188=CIRCLE('',#1187,9.24999999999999);
#1189=CARTESIAN_POINT('',(120.,10.5,-160.75));
#1190=VERTEX_POINT('',#1189);
#1191=EDGE_CURVE('E262',#1190,#1190,#1188,.T.);
#1192=ORIENTED_EDGE('',*,*,#1191,.F.);
#1193=EDGE_LOOP('',(#1192));
#1194=FACE_BOUND('',#1193,.T.);
#1195=ORIENTED_EDGE('',*,*,#407,.T.);
#1196=EDGE_LOOP('',(#1195));
#1197=FACE_BOUND('',#1196,.T.);
#1198=ADVANCED_FACE('F439',(#1194,#1197),#1183,.F.);
#1199=CARTESIAN_POINT('',(126.,10.5,-170.));
#1200=DIRECTION('',(0.,-1.,0.));
#1201=DIRECTION('',(0.,0.,-1.));
#1202=AXIS2_PLACEMENT_3D('',#1199,#1200,#1201);
#1203=PLANE('',#1202);
#1204=CARTESIAN_POINT('',(120.,10.5,-170.));
#1205=DIRECTION('',(0.,1.,0.));
#1206=DIRECTION('',(0.,0.,1.));
#1207=AXIS2_PLACEMENT_3D('',#1204,#1205,#1206);
#1208=CIRCLE('',#1207,6.00000000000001);
#1209=CARTESIAN_POINT('',(120.,10.5,-164.));
#1210=VERTEX_POINT('',#1209);
#1211=EDGE_CURVE('E259',#1210,#1210,#1208,.T.);
#1212=ORIENTED_EDGE('',*,*,#1211,.F.);
#1213=EDGE_LOOP('',(#1212));
#1214=FACE_BOUND('',#1213,.T.);
#1215=ORIENTED_EDGE('',*,*,#1191,.T.);
#1216=EDGE_LOOP('',(#1215));
#1217=FACE_BOUND('',#1216,.T.);
#1218=ADVANCED_FACE('F452',(#1214,#1217),#1203,.F.);
#1219=CARTESIAN_POINT('',(120.,16.,-170.));
#1220=DIRECTION('',(0.,1.,0.));
#1221=DIRECTION('',(0.,0.,1.));
#1222=AXIS2_PLACEMENT_3D('',#1219,#1220,#1221);
#1223=CYLINDRICAL_SURFACE('',#1222,6.);
#1224=ORIENTED_EDGE('',*,*,#599,.F.);
#1225=EDGE_LOOP('',(#1224));
#1226=FACE_BOUND('',#1225,.T.);
#1227=ORIENTED_EDGE('',*,*,#1211,.T.);
#1228=EDGE_LOOP('',(#1227));
#1229=FACE_BOUND('',#1228,.T.);
#1230=ADVANCED_FACE('F448',(#1226,#1229),#1223,.F.);
#1231=CARTESIAN_POINT('',(170.,16.,-20.));
#1232=DIRECTION('',(0.,1.,0.));
#1233=DIRECTION('',(0.,0.,1.));
#1234=AXIS2_PLACEMENT_3D('',#1231,#1232,#1233);
#1235=CYLINDRICAL_SURFACE('',#1234,9.24999999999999);
#1236=CARTESIAN_POINT('',(170.,10.5,-20.));
#1237=DIRECTION('',(0.,1.,0.));
#1238=DIRECTION('',(0.,0.,1.));
#1239=AXIS2_PLACEMENT_3D('',#1236,#1237,#1238);
#1240=CIRCLE('',#1239,9.24999999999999);
#1241=CARTESIAN_POINT('',(170.,10.5,-10.75));
#1242=VERTEX_POINT('',#1241);
#1243=EDGE_CURVE('E274',#1242,#1242,#1240,.T.);
#1244=ORIENTED_EDGE('',*,*,#1243,.F.);
#1245=EDGE_LOOP('',(#1244));
#1246=FACE_BOUND('',#1245,.T.);
#1247=ORIENTED_EDGE('',*,*,#418,.T.);
#1248=EDGE_LOOP('',(#1247));
#1249=FACE_BOUND('',#1248,.T.);
#1250=ADVANCED_FACE('F451',(#1246,#1249),#1235,.F.);
#1251=CARTESIAN_POINT('',(176.,10.5,-20.));
#1252=DIRECTION('',(0.,-1.,0.));
#1253=DIRECTION('',(0.,0.,-1.));
#1254=AXIS2_PLACEMENT_3D('',#1251,#1252,#1253);
#1255=PLANE('',#1254);
#1256=CARTESIAN_POINT('',(170.,10.5,-20.));
#1257=DIRECTION('',(0.,1.,0.));
#1258=DIRECTION('',(0.,0.,1.));
#1259=AXIS2_PLACEMENT_3D('',#1256,#1257,#1258);
#1260=CIRCLE('',#1259,6.00000000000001);
#1261=CARTESIAN_POINT('',(170.,10.5,-14.));
#1262=VERTEX_POINT('',#1261);
#1263=EDGE_CURVE('E271',#1262,#1262,#1260,.T.);
#1264=ORIENTED_EDGE('',*,*,#1263,.F.);
#1265=EDGE_LOOP('',(#1264));
#1266=FACE_BOUND('',#1265,.T.);
#1267=ORIENTED_EDGE('',*,*,#1243,.T.);
#1268=EDGE_LOOP('',(#1267));
#1269=FACE_BOUND('',#1268,.T.);
#1270=ADVANCED_FACE('F464',(#1266,#1269),#1255,.F.);
#1271=CARTESIAN_POINT('',(170.,16.,-20.));
#1272=DIRECTION('',(0.,1.,0.));
#1273=DIRECTION('',(0.,0.,1.));
#1274=AXIS2_PLACEMENT_3D('',#1271,#1272,#1273);
#1275=CYLINDRICAL_SURFACE('',#1274,6.);
#1276=ORIENTED_EDGE('',*,*,#610,.F.);
#1277=EDGE_LOOP('',(#1276));
#1278=FACE_BOUND('',#1277,.T.);
#1279=ORIENTED_EDGE('',*,*,#1263,.T.);
#1280=EDGE_LOOP('',(#1279));
#1281=FACE_BOUND('',#1280,.T.);
#1282=ADVANCED_FACE('F460',(#1278,#1281),#1275,.F.);
#1283=CARTESIAN_POINT('',(220.,16.,-20.));
#1284=DIRECTION('',(0.,1.,0.));
#1285=DIRECTION('',(0.,0.,1.));
#1286=AXIS2_PLACEMENT_3D('',#1283,#1284,#1285);
#1287=CYLINDRICAL_SURFACE('',#1286,9.24999999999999);
#1288=CARTESIAN_POINT('',(220.,10.5,-20.));
#1289=DIRECTION('',(0.,1.,0.));
#1290=DIRECTION('',(0.,0.,1.));
#1291=AXIS2_PLACEMENT_3D('',#1288,#1289,#1290);
#1292=CIRCLE('',#1291,9.24999999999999);
#1293=CARTESIAN_POINT('',(220.,10.5,-10.75));
#1294=VERTEX_POINT('',#1293);
#1295=EDGE_CURVE('E286',#1294,#1294,#1292,.T.);
#1296=ORIENTED_EDGE('',*,*,#1295,.F.);
#1297=EDGE_LOOP('',(#1296));
#1298=FACE_BOUND('',#1297,.T.);
#1299=ORIENTED_EDGE('',*,*,#429,.T.);
#1300=EDGE_LOOP('',(#1299));
#1301=FACE_BOUND('',#1300,.T.);
#1302=ADVANCED_FACE('F463',(#1298,#1301),#1287,.F.);
#1303=CARTESIAN_POINT('',(226.,10.5,-20.));
#1304=DIRECTION('',(0.,-1.,0.));
#1305=DIRECTION('',(0.,0.,-1.));
#1306=AXIS2_PLACEMENT_3D('',#1303,#1304,#1305);
#1307=PLANE('',#1306);
#1308=CARTESIAN_POINT('',(220.,10.5,-20.));
#1309=DIRECTION('',(0.,1.,0.));
#1310=DIRECTION('',(0.,0.,1.));
#1311=AXIS2_PLACEMENT_3D('',#1308,#1309,#1310);
#1312=CIRCLE('',#1311,6.00000000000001);
#1313=CARTESIAN_POINT('',(220.,10.5,-14.));
#1314=VERTEX_POINT('',#1313);
#1315=EDGE_CURVE('E283',#1314,#1314,#1312,.T.);
#1316=ORIENTED_EDGE('',*,*,#1315,.F.);
#1317=EDGE_LOOP('',(#1316));
#1318=FACE_BOUND('',#1317,.T.);
#1319=ORIENTED_EDGE('',*,*,#1295,.T.);
#1320=EDGE_LOOP('',(#1319));
#1321=FACE_BOUND('',#1320,.T.);
#1322=ADVANCED_FACE('F476',(#1318,#1321),#1307,.F.);
#1323=CARTESIAN_POINT('',(220.,16.,-20.));
#1324=DIRECTION('',(0.,1.,0.));
#1325=DIRECTION('',(0.,0.,1.));
#1326=AXIS2_PLACEMENT_3D('',#1323,#1324,#1325);
#1327=CYLINDRICAL_SURFACE('',#1326,6.);
#1328=ORIENTED_EDGE('',*,*,#621,.F.);
#1329=EDGE_LOOP('',(#1328));
#1330=FACE_BOUND('',#1329,.T.);
#1331=ORIENTED_EDGE('',*,*,#1315,.T.);
#1332=EDGE_LOOP('',(#1331));
#1333=FACE_BOUND('',#1332,.T.);
#1334=ADVANCED_FACE('F472',(#1330,#1333),#1327,.F.);
#1335=CARTESIAN_POINT('',(220.,16.,-70.));
#1336=DIRECTION('',(0.,1.,0.));
#1337=DIRECTION('',(0.,0.,1.));
#1338=AXIS2_PLACEMENT_3D('',#1335,#1336,#1337);
#1339=CYLINDRICAL_SURFACE('',#1338,9.24999999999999);
#1340=CARTESIAN_POINT('',(220.,10.5,-70.));
#1341=DIRECTION('',(0.,1.,0.));
#1342=DIRECTION('',(0.,0.,1.));
#1343=AXIS2_PLACEMENT_3D('',#1340,#1341,#1342);
#1344=CIRCLE('',#1343,9.24999999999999);
#1345=CARTESIAN_POINT('',(220.,10.5,-60.75));
#1346=VERTEX_POINT('',#1345);
#1347=EDGE_CURVE('E298',#1346,#1346,#1344,.T.);
#1348=ORIENTED_EDGE('',*,*,#1347,.F.);
#1349=EDGE_LOOP('',(#1348));
#1350=FACE_BOUND('',#1349,.T.);
#1351=ORIENTED_EDGE('',*,*,#440,.T.);
#1352=EDGE_LOOP('',(#1351));
#1353=FACE_BOUND('',#1352,.T.);
#1354=ADVANCED_FACE('F475',(#1350,#1353),#1339,.F.);
#1355=CARTESIAN_POINT('',(226.,10.5,-70.));
#1356=DIRECTION('',(0.,-1.,0.));
#1357=DIRECTION('',(0.,0.,-1.));
#1358=AXIS2_PLACEMENT_3D('',#1355,#1356,#1357);
#1359=PLANE('',#1358);
#1360=CARTESIAN_POINT('',(220.,10.5,-70.));
#1361=DIRECTION('',(0.,1.,0.));
#1362=DIRECTION('',(0.,0.,1.));
#1363=AXIS2_PLACEMENT_3D('',#1360,#1361,#1362);
#1364=CIRCLE('',#1363,6.00000000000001);
#1365=CARTESIAN_POINT('',(220.,10.5,-64.));
#1366=VERTEX_POINT('',#1365);
#1367=EDGE_CURVE('E295',#1366,#1366,#1364,.T.);
#1368=ORIENTED_EDGE('',*,*,#1367,.F.);
#1369=EDGE_LOOP('',(#1368));
#1370=FACE_BOUND('',#1369,.T.);
#1371=ORIENTED_EDGE('',*,*,#1347,.T.);
#1372=EDGE_LOOP('',(#1371));
#1373=FACE_BOUND('',#1372,.T.);
#1374=ADVANCED_FACE('F488',(#1370,#1373),#1359,.F.);
#1375=CARTESIAN_POINT('',(220.,16.,-70.));
#1376=DIRECTION('',(0.,1.,0.));
#1377=DIRECTION('',(0.,0.,1.));
#1378=AXIS2_PLACEMENT_3D('',#1375,#1376,#1377);
#1379=CYLINDRICAL_SURFACE('',#1378,6.);
#1380=ORIENTED_EDGE('',*,*,#632,.F.);
#1381=EDGE_LOOP('',(#1380));
#1382=FACE_BOUND('',#1381,.T.);
#1383=ORIENTED_EDGE('',*,*,#1367,.T.);
#1384=EDGE_LOOP('',(#1383));
#1385=FACE_BOUND('',#1384,.T.);
#1386=ADVANCED_FACE('F484',(#1382,#1385),#1379,.F.);
#1387=CARTESIAN_POINT('',(220.,16.,-120.));
#1388=DIRECTION('',(0.,1.,0.));
#1389=DIRECTION('',(0.,0.,1.));
#1390=AXIS2_PLACEMENT_3D('',#1387,#1388,#1389);
#1391=CYLINDRICAL_SURFACE('',#1390,9.24999999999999);
#1392=CARTESIAN_POINT('',(220.,10.5,-120.));
#1393=DIRECTION('',(0.,1.,0.));
#1394=DIRECTION('',(0.,0.,1.));
#1395=AXIS2_PLACEMENT_3D('',#1392,#1393,#1394);
#1396=CIRCLE('',#1395,9.24999999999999);
#1397=CARTESIAN_POINT('',(220.,10.5,-110.75));
#1398=VERTEX_POINT('',#1397);
#1399=EDGE_CURVE('E310',#1398,#1398,#1396,.T.);
#1400=ORIENTED_EDGE('',*,*,#1399,.F.);
#1401=EDGE_LOOP('',(#1400));
#1402=FACE_BOUND('',#1401,.T.);
#1403=ORIENTED_EDGE('',*,*,#451,.T.);
#1404=EDGE_LOOP('',(#1403));
#1405=FACE_BOUND('',#1404,.T.);
#1406=ADVANCED_FACE('F487',(#1402,#1405),#1391,.F.);
#1407=CARTESIAN_POINT('',(226.,10.5,-120.));
#1408=DIRECTION('',(0.,-1.,0.));
#1409=DIRECTION('',(0.,0.,-1.));
#1410=AXIS2_PLACEMENT_3D('',#1407,#1408,#1409);
#1411=PLANE('',#1410);
#1412=CARTESIAN_POINT('',(220.,10.5,-120.));
#1413=DIRECTION('',(0.,1.,0.));
#1414=DIRECTION('',(0.,0.,1.));
#1415=AXIS2_PLACEMENT_3D('',#1412,#1413,#1414);
#1416=CIRCLE('',#1415,6.00000000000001);
#1417=CARTESIAN_POINT('',(220.,10.5,-114.));
#1418=VERTEX_POINT('',#1417);
#1419=EDGE_CURVE('E307',#1418,#1418,#1416,.T.);
#1420=ORIENTED_EDGE('',*,*,#1419,.F.);
#1421=EDGE_LOOP('',(#1420));
#1422=FACE_BOUND('',#1421,.T.);
#1423=ORIENTED_EDGE('',*,*,#1399,.T.);
#1424=EDGE_LOOP('',(#1423));
#1425=FACE_BOUND('',#1424,.T.);
#1426=ADVANCED_FACE('F498',(#1422,#1425),#1411,.F.);
#1427=CARTESIAN_POINT('',(220.,16.,-120.));
#1428=DIRECTION('',(0.,1.,0.));
#1429=DIRECTION('',(0.,0.,1.));
#1430=AXIS2_PLACEMENT_3D('',#1427,#1428,#1429);
#1431=CYLINDRICAL_SURFACE('',#1430,6.);
#1432=ORIENTED_EDGE('',*,*,#643,.F.);
#1433=EDGE_LOOP('',(#1432));
#1434=FACE_BOUND('',#1433,.T.);
#1435=ORIENTED_EDGE('',*,*,#1419,.T.);
#1436=EDGE_LOOP('',(#1435));
#1437=FACE_BOUND('',#1436,.T.);
#1438=ADVANCED_FACE('F330',(#1434,#1437),#1431,.F.);
#1439=CARTESIAN_POINT('',(220.,16.,-170.));
#1440=DIRECTION('',(0.,1.,0.));
#1441=DIRECTION('',(0.,0.,1.));
#1442=AXIS2_PLACEMENT_3D('',#1439,#1440,#1441);
#1443=CYLINDRICAL_SURFACE('',#1442,9.24999999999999);
#1444=CARTESIAN_POINT('',(220.,10.5,-170.));
#1445=DIRECTION('',(0.,1.,0.));
#1446=DIRECTION('',(0.,0.,1.));
#1447=AXIS2_PLACEMENT_3D('',#1444,#1445,#1446);
#1448=CIRCLE('',#1447,9.24999999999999);
#1449=CARTESIAN_POINT('',(220.,10.5,-160.75));
#1450=VERTEX_POINT('',#1449);
#1451=EDGE_CURVE('E11',#1450,#1450,#1448,.T.);
#1452=ORIENTED_EDGE('',*,*,#1451,.F.);
#1453=EDGE_LOOP('',(#1452));
#1454=FACE_BOUND('',#1453,.T.);
#1455=ORIENTED_EDGE('',*,*,#462,.T.);
#1456=EDGE_LOOP('',(#1455));
#1457=FACE_BOUND('',#1456,.T.);
#1458=ADVANCED_FACE('F35',(#1454,#1457),#1443,.F.);
#1459=CARTESIAN_POINT('',(226.,10.5,-170.));
#1460=DIRECTION('',(0.,-1.,0.));
#1461=DIRECTION('',(0.,0.,-1.));
#1462=AXIS2_PLACEMENT_3D('',#1459,#1460,#1461);
#1463=PLANE('',#1462);
#1464=CARTESIAN_POINT('',(220.,10.5,-170.));
#1465=DIRECTION('',(0.,1.,0.));
#1466=DIRECTION('',(0.,0.,1.));
#1467=AXIS2_PLACEMENT_3D('',#1464,#1465,#1466);
#1468=CIRCLE('',#1467,6.00000000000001);
#1469=CARTESIAN_POINT('',(220.,10.5,-164.));
#1470=VERTEX_POINT('',#1469);
#1471=EDGE_CURVE('E41',#1470,#1470,#1468,.T.);
#1472=ORIENTED_EDGE('',*,*,#1471,.F.);
#1473=EDGE_LOOP('',(#1472));
#1474=FACE_BOUND('',#1473,.T.);
#1475=ORIENTED_EDGE('',*,*,#1451,.T.);
#1476=EDGE_LOOP('',(#1475));
#1477=FACE_BOUND('',#1476,.T.);
#1478=ADVANCED_FACE('F323',(#1474,#1477),#1463,.F.);
#1479=CARTESIAN_POINT('',(220.,16.,-170.));
#1480=DIRECTION('',(0.,1.,0.));
#1481=DIRECTION('',(0.,0.,1.));
#1482=AXIS2_PLACEMENT_3D('',#1479,#1480,#1481);
#1483=CYLINDRICAL_SURFACE('',#1482,6.);
#1484=ORIENTED_EDGE('',*,*,#654,.F.);
#1485=EDGE_LOOP('',(#1484));
#1486=FACE_BOUND('',#1485,.T.);
#1487=ORIENTED_EDGE('',*,*,#1471,.T.);
#1488=EDGE_LOOP('',(#1487));
#1489=FACE_BOUND('',#1488,.T.);
#1490=ADVANCED_FACE('F321',(#1486,#1489),#1483,.F.);
#1491=CLOSED_SHELL('',(#60,#91,#124,#155,#188,#219,#252,#274,#466,#658,#678,#698,#710,#730,#750,
#762,#782,#802,#814,#834,#854,#866,#886,#906,#918,#938,#958,#970,#990,#1010,#1022,#1042,#1062,
#1074,#1094,#1114,#1126,#1146,#1166,#1178,#1198,#1218,#1230,#1250,#1270,#1282,#1302,#1322,#1334,
#1354,#1374,#1386,#1406,#1426,#1438,#1458,#1478,#1490));
#1492=MANIFOLD_SOLID_BREP('B2',#1491);
#1493=ADVANCED_BREP_SHAPE_REPRESENTATION('',(#18,#1492),#14);
#1494=SHAPE_DEFINITION_REPRESENTATION(#9,#1493);
ENDSEC;
END-ISO-10303-21;
